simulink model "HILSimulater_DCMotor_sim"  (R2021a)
settings: Solver=ode1  StartTime=0.0  StopTime=inf  FixedStep=10e-3  RelTol=1e-3  EnableMultiTasking=on
libraries: arduinolib x19

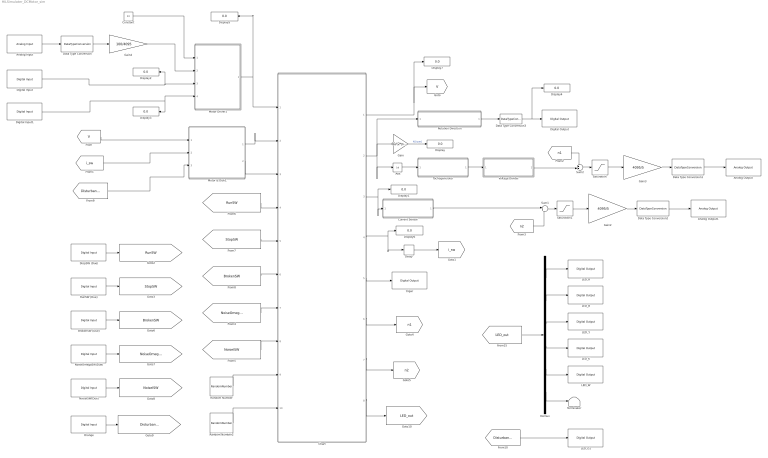
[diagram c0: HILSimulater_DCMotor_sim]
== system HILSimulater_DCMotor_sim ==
  Abs : Abs
  Analog Input : arduinolib/Analog Input  pinNumber=8  ReadResultsOnly=off  ConversionTriggerSource=Software  ExternalTriggerType=uint32( 0 )  OutputDataType=uint16  EnableConversionCompleteNotify=off  EnableOuputStatus=off  SampleTime=-1  blockPlatform=arduino
  Analog Output : arduinolib/Analog Output  DACpin=DAC0  blockPlatform=arduino
  Analog Output1 : arduinolib/Analog Output  DACpin=DAC1  blockPlatform=arduino
  BrokenSW (Due) : arduinolib/Digital Input  pinNumber=16  mode=Default  Direction=input  SampleTime=-1  blockPlatform=arduino
  Chart : Stateflow chart  TreatAsAtomicUnit=on
  Constant : Constant  Value=24
  Current Sensor : Subsystem  mask(電流センサモデル){}
  Data Type Conversion : DataTypeConversion  OutDataTypeStr=double
  Data Type Conversion1 : DataTypeConversion  OutDataTypeStr=uint16
  Data Type Conversion2 : DataTypeConversion  OutDataTypeStr=uint16
  Data Type Conversion3 : DataTypeConversion  OutDataTypeStr=uint8
  Delay : Delay  DelayLength=1  InitialCondition=0
  Demux : Demux  Outputs=6
  Digital Input : arduinolib/Digital Input  pinNumber=6  mode=Default  Direction=input  SampleTime=-1  blockPlatform=arduino
  Digital Input1 : arduinolib/Digital Input  pinNumber=5  mode=Default  Direction=input  SampleTime=-1  blockPlatform=arduino
  Digital Output : arduinolib/Digital Output  pinNumber=2  Direction=output  blockPlatform=arduino
  Display{,1..7} (8 alike) : Display
  Gain : Gain  Gain=60/(2*pi)
  Gain2 : Gain  Gain=4095/5
  Gain3 : Gain  Gain=4095/5
  Gain4 : Gain  Gain=100/4095
  LED_B : arduinolib/Digital Output  pinNumber=9  Direction=output  blockPlatform=arduino
  LED_K : arduinolib/Digital Output  pinNumber=13  Direction=output  blockPlatform=arduino
  LED_O1 : arduinolib/Digital Output  pinNumber=11  Direction=output  blockPlatform=arduino
  LED_R : arduinolib/Digital Output  pinNumber=8  Direction=output  blockPlatform=arduino
  LED_W : arduinolib/Digital Output  pinNumber=12  Direction=output  blockPlatform=arduino
  LED_Y : arduinolib/Digital Output  pinNumber=10  Direction=output  blockPlatform=arduino
  Motor & Disk1 : Subsystem  mask(モータ＆プラントモデル){R=5.7, L=0.2, J_M=0.11e-3, J_I=1.3e-3, D=6.0e-5, K_tau=7.2e-2, K_e=7.2e-2}
      mask prompts: R "電気子抵抗：R"; L "インダクタンス：L"; J_M "電気子の慣性モーメント：J_M"; J_I "負荷の慣性モーメント:J_I"; D "粘性抵抗係数：D"; K_tau "トルク定数：K_tau"; K_e "逆起電力定数：K_e"
  Motor Driver1 : Subsystem  mask(モータドライバモデル){}
  NoiseISW(Due) : arduinolib/Digital Input  pinNumber=18  mode=Default  Direction=input  SampleTime=-1  blockPlatform=arduino
  NoiseOmegaSW(Due) : arduinolib/Digital Input  pinNumber=19  mode=Default  Direction=input  SampleTime=-1  blockPlatform=arduino
  Orange : arduinolib/Digital Input  pinNumber=17  mode=Default  Direction=input  SampleTime=-1  blockPlatform=arduino
  Random Number : RandomNumber  Variance=1.0^2
  Random Number2 : RandomNumber  Variance=1.0^2
  Rotation Direction : Subsystem
  RunSW (Due) : arduinolib/Digital Input  pinNumber=14  mode=Default  Direction=input  SampleTime=-1  blockPlatform=arduino
  Saturation : Saturate  UpperLimit=5  LowerLimit=0
  Saturation1 : Saturate  UpperLimit=5  LowerLimit=0
  StopSW (Due) : arduinolib/Digital Input  pinNumber=15  mode=Default  Direction=input  SampleTime=-1  blockPlatform=arduino
  Sum1 : Sum  Inputs=|++
  Sum2 : Sum  Inputs=++|
  Tachogenerator : Subsystem  mask(タコジェネレータモデル){}
  Terminator : Terminator
  Voltage Divider : Subsystem  mask(A/D変換器モデル){alpha=0.5}
      mask prompts: alpha "電圧変換係数: alpha"
  trigar : arduinolib/Digital Output  pinNumber=7  Direction=output  blockPlatform=arduino
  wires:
  Motor & Disk1/2(i_M [A]) -> Chart/3(i_in)
  Motor & Disk1/1(omega [rad/s]) -> Chart/2(omega_in)
  Motor Driver1/1(v_M [V]) -> Display5/1, Chart/1(V_in)
  Chart/4(i_sw) -> Delay/1, Display6/1
  Chart/2(omega_out) -> Abs/1, Gain/1, Rotation Direction/1(V_M [V])
  Chart/5(flag_RUN) -> trigar/1
  [V] -> Motor & Disk1/1(v_M [V])
  [i_sw] -> Motor & Disk1/2(i_SW [1/0])
  Delay/1 -> [i_sw]
  Gain2/1 -> Data Type Conversion2/1
  Data Type Conversion1/1 -> Analog Output/1
  Data Type Conversion2/1 -> Analog Output1/1
  [n1] -> Sum2/1
  Gain3/1 -> Data Type Conversion1/1
  Sum2/1 -> Saturation/1
  Tachogenerator/1(v_T [V]) -> Voltage Divider/1(v_T [V])
  Random Number/1 -> Chart/9(noise_omega_in)
  Chart/6(noise_omega_out) -> [n1]
  Chart/7(noise_i_out) -> [n2]
  Random Number2/1 -> Chart/10(noise_i_in)
  StopSW (Due)/1 -> [RunSW]
  RunSW (Due)/1 -> [StopSW]
  BrokenSW (Due)/1 -> [BrokenSW]
  NoiseOmegaSW(Due)/1 -> [NoiseOmegaSW]
  NoiseISW(Due)/1 -> [NoiseISW]
  [NoiseISW] -> Chart/8(Noise_i_SW)
  [NoiseOmegaSW] -> Chart/7(Noise_omega_SW)
  [BrokenSW] -> Chart/6(Broken_SW)
  Orange/1 -> [Disturbance]
  [StopSW] -> Chart/5(Stop_SW)
  [RunSW] -> Chart/4(Run_SW)
  Demux/1 -> LED_R/1
  Demux/2 -> LED_B/1
  Demux/3 -> LED_Y/1
  Demux/4 -> LED_K/1
  Demux/5 -> LED_W/1
  Demux/6 -> Terminator/1
  Chart/8(LED_out) -> [LED_out]
  [LED_out] -> Demux/1
  Chart/3(i_out) -> Display1/1, Current Sensor/1(i [A])
  Sum1/1 -> Saturation1/1
  Saturation/1 -> Gain3/1
  Saturation1/1 -> Gain2/1
  [Disturbance] -> Motor & Disk1/3(dis)
  [Disturbance] -> LED_O1/1
  Analog Input/1 -> Data Type Conversion/1
  Data Type Conversion/1 -> Gain4/1
  Gain4/1 -> Motor Driver1/2(u_MD [%])
  Constant/1 -> Motor Driver1/1(Vs [V])
  Digital Input/1 -> Display2/1, Motor Driver1/3(CW [0/1])
  Digital Input1/1 -> Display3/1, Motor Driver1/4(CCW [0/1])
  Voltage Divider/1(v_N [-]) -> Sum2/2
  Gain/1 -> Display/1  "N [rpm]"
  Chart/1(V_out) -> Display7/1, [V]
  Rotation Direction/1(Direction [CW/CCW]) -> Data Type Conversion3/1
  Data Type Conversion3/1 -> Digital Output/1, Display4/1
  Current Sensor/1(v_i [V]) -> Sum1/1
  [n2] -> Sum1/2
  Abs/1 -> Tachogenerator/1(omega [rad/s])

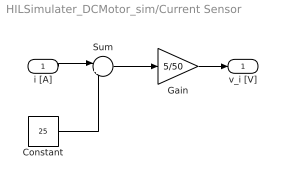
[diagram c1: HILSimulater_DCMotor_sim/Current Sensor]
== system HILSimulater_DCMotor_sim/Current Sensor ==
  i [A] : Inport
  Constant : Constant  Value=25
  Gain : Gain  Gain=5/50
  Sum : Sum  Inputs=|++
  v_i [V] : Outport
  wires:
  i [A]/1 -> Sum/1
  Gain/1 -> v_i [V]/1
  Constant/1 -> Sum/2
  Sum/1 -> Gain/1

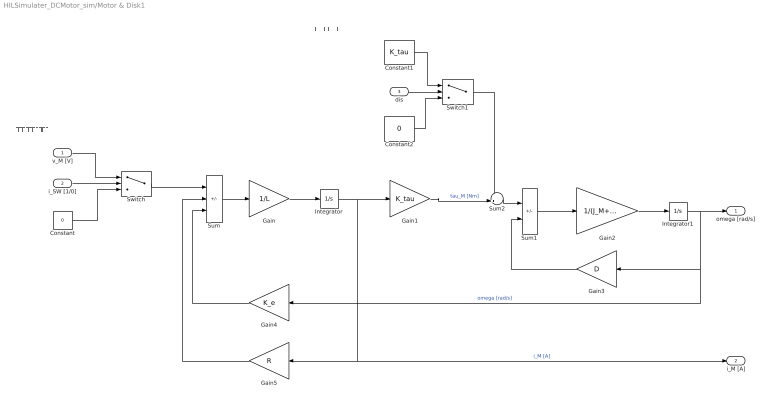
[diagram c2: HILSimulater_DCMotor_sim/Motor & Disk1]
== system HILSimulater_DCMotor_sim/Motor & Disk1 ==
  note: 電源スイッチ連動模擬
  note: ステップ状外乱
  v_M [V] : Inport
  i_SW [1/0] : Inport  Port=2
  dis : Inport  Port=3
  Constant : Constant  Value=0
  Constant1 : Constant  Value=K_tau
  Constant2 : Constant  Value=0
  Gain : Gain  Gain=1/L
  Gain1 : Gain  Gain=K_tau
  Gain2 : Gain  Gain=1/(J_M+J_I)
  Gain3 : Gain  Gain=D
  Gain4 : Gain  Gain=K_e
  Gain5 : Gain  Gain=R
  Integrator : Integrator
  Integrator1 : Integrator
  Sum : Sum  Inputs=+--
  Sum1 : Sum  Inputs=+-
  Sum2 : Sum  Inputs=-+|
  Switch : Switch  Criteria=u2 > Threshold  Threshold=0.5
  Switch1 : Switch  Criteria=u2 > Threshold  Threshold=0.5
  omega [rad/s] : Outport
  i_M [A] : Outport  Port=2
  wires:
  Gain3/1 -> Sum1/2
  Gain4/1 -> Sum/3
  Integrator1/1 -> omega [rad/s]/1, Gain3/1, Gain4/1  "omega [rad/s]"
  Gain2/1 -> Integrator1/1
  Sum1/1 -> Gain2/1
  Gain1/1 -> Sum2/2  "tau_M [Nm]"
  Gain5/1 -> Sum/2
  Integrator/1 -> Gain5/1, i_M [A]/1, Gain1/1  "i_M [A]"
  Gain/1 -> Integrator/1
  Sum/1 -> Gain/1
  v_M [V]/1 -> Switch/1
  i_SW [1/0]/1 -> Switch/2
  Switch/1 -> Sum/1
  Constant/1 -> Switch/3
  Sum2/1 -> Sum1/1
  dis/1 -> Switch1/2
  Switch1/1 -> Sum2/1
  Constant1/1 -> Switch1/1
  Constant2/1 -> Switch1/3

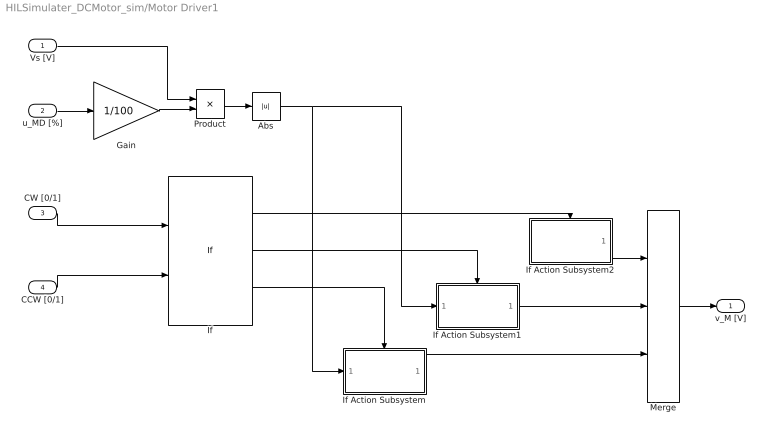
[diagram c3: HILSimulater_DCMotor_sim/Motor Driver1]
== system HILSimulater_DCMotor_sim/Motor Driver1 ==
  Vs [V] : Inport
  u_MD [%] : Inport  Port=2
  CW [0/1] : Inport  Port=3
  CCW [0/1] : Inport  Port=4
  Abs : Abs
  Gain : Gain  Gain=1/100
  If : If  NumInputs=2  IfExpression=u1 == u2  ElseIfExpressions=u1 == 1
  If Action Subsystem : Subsystem  TreatAsAtomicUnit=on
  If Action Subsystem1 : Subsystem  TreatAsAtomicUnit=on
  If Action Subsystem2 : Subsystem  TreatAsAtomicUnit=on
  Merge : Merge  Inputs=3  InitialOutput=[0]
  Product : Product
  v_M [V] : Outport
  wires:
  Gain/1 -> Product/2
  Vs [V]/1 -> Product/1
  Product/1 -> Abs/1
  u_MD [%]/1 -> Gain/1
  Abs/1 -> If Action Subsystem/1(|v_M| [V]), If Action Subsystem1/1(|v_M| [V])
  CW [0/1]/1 -> If/1
  CCW [0/1]/1 -> If/2
  If/3 -> If Action Subsystem/Action
  If Action Subsystem/1(-v_M [V]) -> Merge/3
  If Action Subsystem1/1(v_M [V]) -> Merge/2
  If Action Subsystem2/1(0 [V]) -> Merge/1
  If/2 -> If Action Subsystem1/Action
  If/1 -> If Action Subsystem2/Action
  Merge/1 -> v_M [V]/1

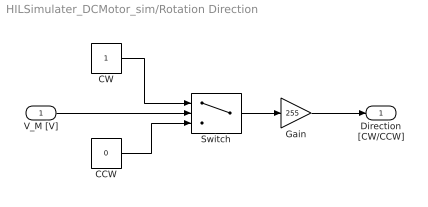
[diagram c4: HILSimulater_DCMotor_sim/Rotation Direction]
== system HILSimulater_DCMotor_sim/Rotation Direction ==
  V_M [V] : Inport
  CCW : Constant  Value=0
  CW : Constant
  Gain : Gain  Gain=255
  Switch : Switch  Criteria=u2 > Threshold
  Direction [CW/CCW] : Outport
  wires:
  V_M [V]/1 -> Switch/2
  Switch/1 -> Gain/1
  CW/1 -> Switch/1
  CCW/1 -> Switch/3
  Gain/1 -> Direction [CW/CCW]/1

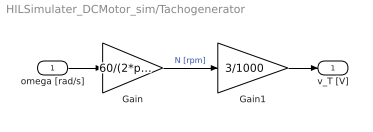
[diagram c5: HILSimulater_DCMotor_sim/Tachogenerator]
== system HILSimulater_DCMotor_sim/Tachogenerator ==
  omega [rad/s] : Inport
  Gain : Gain  Gain=60/(2*pi)
  Gain1 : Gain  Gain=3/1000
  v_T [V] : Outport
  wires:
  omega [rad/s]/1 -> Gain/1
  Gain1/1 -> v_T [V]/1
  Gain/1 -> Gain1/1  "N [rpm]"

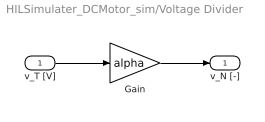
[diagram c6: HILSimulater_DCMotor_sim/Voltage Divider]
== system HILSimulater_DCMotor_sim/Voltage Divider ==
  v_T [V] : Inport
  Gain : Gain  Gain=alpha
  v_N [-] : Outport
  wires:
  v_T [V]/1 -> Gain/1
  Gain/1 -> v_N [-]/1

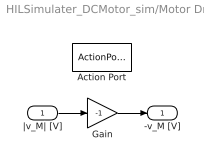
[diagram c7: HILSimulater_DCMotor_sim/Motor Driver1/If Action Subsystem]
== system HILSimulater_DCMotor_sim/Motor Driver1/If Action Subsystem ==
  |v_M| [V] : Inport
  Action Port : ActionPort  ActionPortLabel=else
  Gain : Gain  Gain=-1
  -v_M [V] : Outport
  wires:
  |v_M| [V]/1 -> Gain/1
  Gain/1 -> -v_M [V]/1

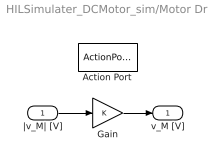
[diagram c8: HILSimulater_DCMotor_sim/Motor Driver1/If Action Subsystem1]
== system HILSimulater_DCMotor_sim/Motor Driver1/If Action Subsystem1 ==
  |v_M| [V] : Inport
  Action Port : ActionPort  ActionPortLabel=elseif(u1 == 1)
  Gain : Gain
  v_M [V] : Outport
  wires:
  |v_M| [V]/1 -> Gain/1
  Gain/1 -> v_M [V]/1

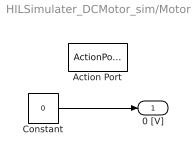
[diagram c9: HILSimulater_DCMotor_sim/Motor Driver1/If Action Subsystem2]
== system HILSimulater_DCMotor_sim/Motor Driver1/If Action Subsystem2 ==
  Action Port : ActionPort  ActionPortLabel=if(u1 == u2)
  Constant : Constant  Value=0
  0 [V] : Outport
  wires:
  Constant/1 -> 0 [V]/1

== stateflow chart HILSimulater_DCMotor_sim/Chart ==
  state Stop
    entry:
    during:
    V_out=0; i_out=i_in; omega_out=omega_in; i_sw=1;flag_RUN=1;
    noise_omega_out=0;noise_i_out=0;
    LED_out=[1 0 0 0 0 0];
    exit:
  state Run
    entry:
    during:
    V_out=V_in; i_out=i_in; omega_out=omega_in; i_sw=1;flag_RUN=0;
    noise_omega_out=0;noise_i_out=0;
    LED_out=[0 1 0 0 0 0];
    exit:
  state Broken
    entry:
    during:
    V_out= V_in/2; i_out=i_in; omega_out=omega_in; i_sw=1;flag_RUN=0;
    noise_omega_out=0;noise_i_out=0;
    LED_out=[0 0 1 0 0 0];
    exit:
  state noise_omega
    entry:
    during:
    V_out=V_in; i_out=i_in; omega_out=omega_in; i_sw=1;flag_RUN=0;
    noise_omega_out=noise_omega_in;noise_i_out=0;
    LED_out=[0 0 0 1 0 0];
    exit:
  state noise_i
    entry:
    during:
    V_out=V_in; i_out=i_in; omega_out=omega_in; i_sw=1;flag_RUN=0;
    noise_omega_out=0;noise_i_out=noise_i_in;
    LED_out=[0 0 0 0 1 0];
    exit:
  (default) -> Stop
  noise_i -> Stop : [Stop_SW==true]
  noise_omega -> Stop : [Stop_SW==true]
  Broken -> Stop : [Stop_SW==true]
  Run -> Stop : [Stop_SW==true]
  Stop -> Run : [Run_SW==true]
  noise_i -> Run : [Run_SW==true]
  Run -> noise_i : [Noise_i_SW==true]
  noise_omega -> Run : [Run_SW==true]
  Run -> noise_omega : [Noise_omega_SW==true]
  Run -> Broken : [Broken_SW==true]
  data: V_out output; V_in input; omega_in input; i_in input; omega_out output; Run_SW input; Stop_SW input; Broken_SW input; i_out output; i_sw output; flag_RUN output; Noise_omega_SW input; Noise_i_SW input; noise_omega_out output; noise_omega_in input; noise_i_out output; noise_i_in input; LED_out output
